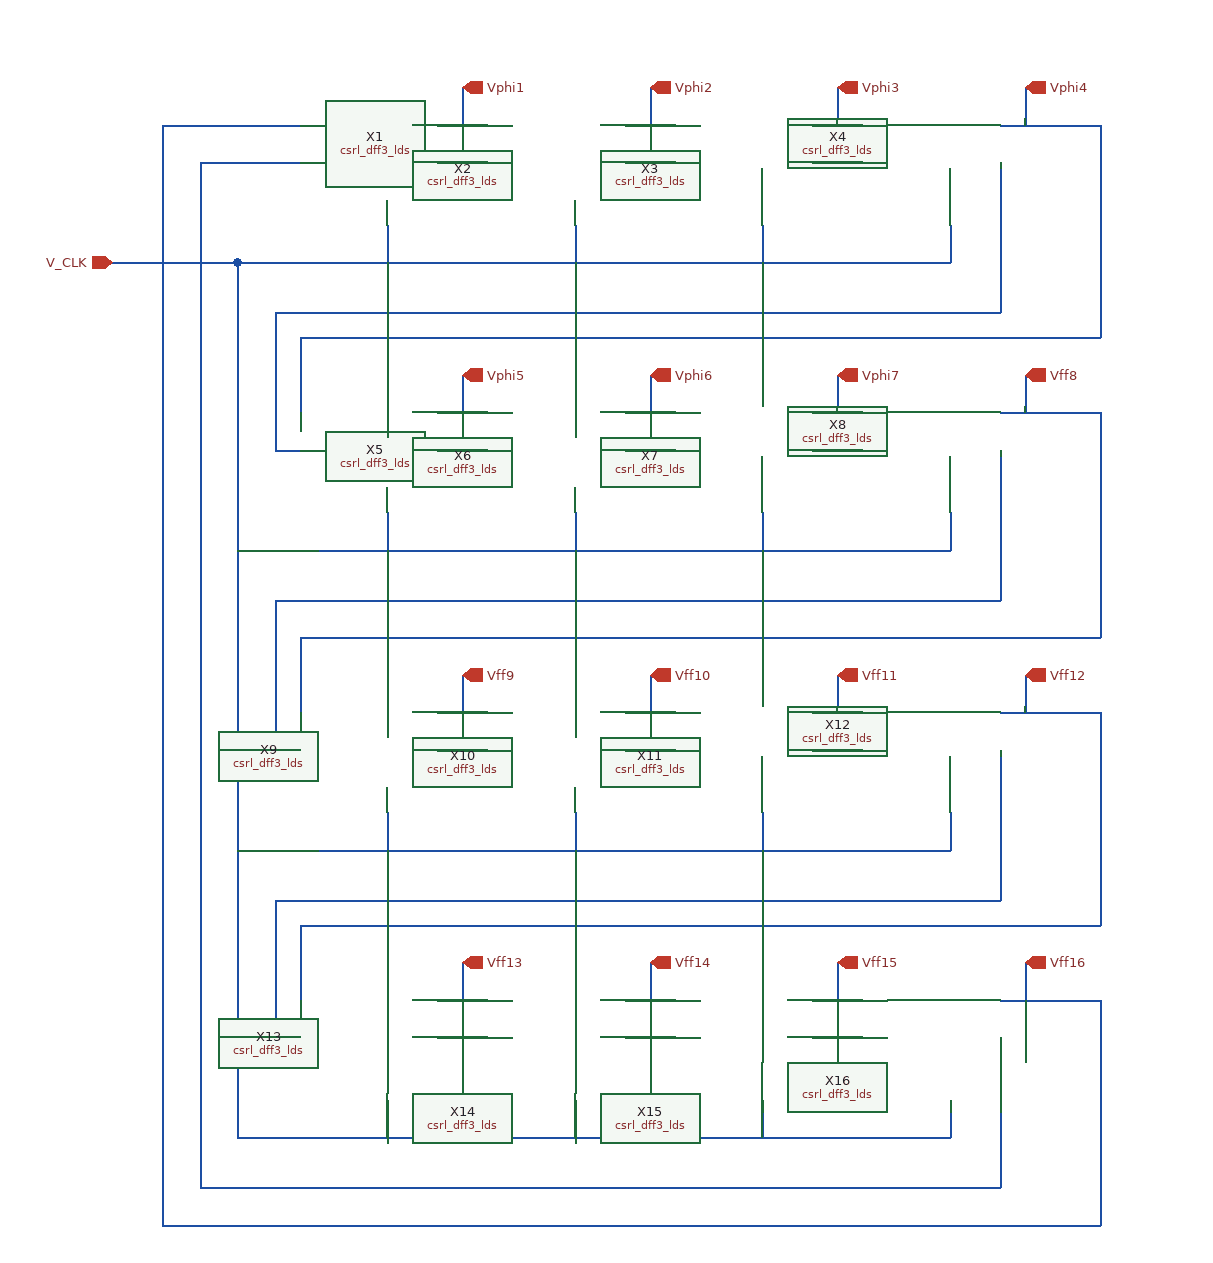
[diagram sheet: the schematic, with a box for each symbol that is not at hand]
v {xschem version=3.4.3 file_version=1.2
}
G {}
K {}
V {}
S {}
E {}
N -10 130 460 130 {
lab=V_CLK}
N 460 100 460 130 {
lab=V_CLK}
N -10 360 460 360 {
lab=V_CLK}
N 460 330 460 360 {
lab=V_CLK}
N 580 140 580 190 {
lab=Vphi4}
N -60 190 580 190 {
lab=Vphi4}
N -80 170 -80 280 {
lab=#net1}
N -80 280 -60 280 {
lab=#net1}
N -10 600 460 600 {
lab=V_CLK}
N 10 570 10 600 {
lab=V_CLK}
N 460 570 460 600 {
lab=V_CLK}
N -10 830 460 830 {
lab=V_CLK}
N 460 800 460 830 {
lab=V_CLK}
N -60 660 580 660 {
lab=Vff12}
N -80 640 -80 750 {
lab=#net2}
N -80 750 -60 750 {
lab=#net2}
N 580 370 580 430 {
lab=Vff8}
N -60 430 580 430 {
lab=Vff8}
N -80 400 -80 520 {
lab=#net3}
N -80 520 -60 520 {
lab=#net3}
N -140 50 -140 870 {
lab=#net4}
N 580 840 580 900 {
lab=Vff16}
N -170 20 -170 900 {
lab=Vff16}
N -60 190 -60 250 {
lab=Vphi4}
N -60 430 -60 490 {
lab=Vff8}
N -60 660 -60 720 {
lab=Vff12}
N 500 50 500 170 {
lab=#net1}
N -80 170 500 170 {
lab=#net1}
N 580 20 580 140 {
lab=Vphi4}
N 580 250 580 370 {
lab=Vff8}
N -80 400 500 400 {
lab=#net3}
N 500 280 500 400 {
lab=#net3}
N 580 490 580 660 {
lab=Vff12}
N 500 520 500 640 {
lab=#net2}
N -80 640 500 640 {
lab=#net2}
N 580 720 580 840 {
lab=Vff16}
N 500 750 500 870 {
lab=#net4}
N -170 20 -60 20 {
lab=Vff16}
N -140 50 -60 50 {
lab=#net4}
N -140 870 500 870 {
lab=#net4}
N -170 900 580 900 {
lab=Vff16}
N -110 130 -10 130 {
lab=V_CLK}
N -110 130 -110 830 {
lab=V_CLK}
N -110 830 -10 830 {
lab=V_CLK}
N -110 600 -10 600 {
lab=V_CLK}
N -110 360 -10 360 {
lab=V_CLK}
N -210 130 -110 130 {
lab=V_CLK}
N 500 20 580 20 {
lab=Vphi4}
N 500 250 580 250 {
lab=Vff8}
N 500 490 580 490 {
lab=Vff12}
N 500 720 580 720 {
lab=Vff16}
N 310 330 310 360 {
lab=V_CLK}
N 160 330 160 360 {
lab=V_CLK}
N 10 330 10 360 {
lab=V_CLK}
N 10 100 10 130 {
lab=V_CLK}
N 160 100 160 130 {
lab=V_CLK}
N 310 100 310 130 {
lab=V_CLK}
N 310 570 310 600 {
lab=V_CLK}
N 160 570 160 600 {
lab=V_CLK}
N 10 800 10 830 {
lab=V_CLK}
N 310 800 310 830 {
lab=V_CLK}
N 160 800 160 830 {
lab=V_CLK}
N 50 20 90 20 {
lab=Vphi1}
N 50 50 90 50 {
lab=#net5}
N 200 20 240 20 {
lab=Vphi2}
N 200 50 240 50 {
lab=#net6}
N 350 20 390 20 {
lab=Vphi3}
N 350 50 390 50 {
lab=#net7}
N 350 250 390 250 {
lab=Vphi7}
N 350 280 390 280 {
lab=#net8}
N 200 250 240 250 {
lab=Vphi6}
N 200 280 240 280 {
lab=#net9}
N 50 280 90 280 {
lab=#net10}
N 50 250 90 250 {
lab=Vphi5}
N 50 520 90 520 {
lab=#net11}
N 50 490 90 490 {
lab=Vff9}
N 200 520 240 520 {
lab=#net12}
N 200 490 240 490 {
lab=Vff10}
N 350 520 390 520 {
lab=#net13}
N 350 490 390 490 {
lab=Vff11}
N 350 750 390 750 {
lab=#net14}
N 350 720 390 720 {
lab=Vff15}
N 200 750 240 750 {
lab=#net15}
N 200 720 240 720 {
lab=Vff14}
N 50 750 90 750 {
lab=#net16}
N 50 720 90 720 {
lab=Vff13}
N 70 -10 70 20 {
lab=Vphi1}
N 220 -10 220 20 {
lab=Vphi2}
N 370 -10 370 20 {
lab=Vphi3}
N 70 220 70 250 {
lab=Vphi5}
N 220 220 220 250 {
lab=Vphi6}
N 370 220 370 250 {
lab=Vphi7}
N 520 -10 520 20 {
lab=Vphi4}
N 520 220 520 250 {
lab=Vff8}
N 520 460 520 490 {
lab=Vff12}
N 520 690 520 720 {
lab=Vff16}
N 70 460 70 490 {
lab=Vff9}
N 220 460 220 490 {
lab=Vff10}
N 370 460 370 490 {
lab=Vff11}
N 370 690 370 720 {
lab=Vff15}
N 220 690 220 720 {
lab=Vff14}
N 70 690 70 720 {
lab=Vff13}
C {/home/madvlsi/VLSI_Sine_Gen/simulation/shift_register/lauren_mp2_files/csrl_dff3_lds.sym} -130 0 0 0 {name=X1}
C {/home/madvlsi/VLSI_Sine_Gen/simulation/shift_register/lauren_mp2_files/csrl_dff3_lds.sym} 20 0 0 0 {name=X2}
C {/home/madvlsi/VLSI_Sine_Gen/simulation/shift_register/lauren_mp2_files/csrl_dff3_lds.sym} 170 0 0 0 {name=X3}
C {/home/madvlsi/VLSI_Sine_Gen/simulation/shift_register/lauren_mp2_files/csrl_dff3_lds.sym} 320 0 0 0 {name=X4}
C {/home/madvlsi/VLSI_Sine_Gen/simulation/shift_register/lauren_mp2_files/csrl_dff3_lds.sym} -130 230 0 0 {name=X5}
C {/home/madvlsi/VLSI_Sine_Gen/simulation/shift_register/lauren_mp2_files/csrl_dff3_lds.sym} 20 230 0 0 {name=X6}
C {/home/madvlsi/VLSI_Sine_Gen/simulation/shift_register/lauren_mp2_files/csrl_dff3_lds.sym} 170 230 0 0 {name=X7}
C {/home/madvlsi/VLSI_Sine_Gen/simulation/shift_register/lauren_mp2_files/csrl_dff3_lds.sym} 320 230 0 0 {name=X8}
C {/home/madvlsi/VLSI_Sine_Gen/simulation/shift_register/lauren_mp2_files/csrl_dff3_lds.sym} -130 470 0 0 {name=X9}
C {/home/madvlsi/VLSI_Sine_Gen/simulation/shift_register/lauren_mp2_files/csrl_dff3_lds.sym} 20 470 0 0 {name=X10}
C {/home/madvlsi/VLSI_Sine_Gen/simulation/shift_register/lauren_mp2_files/csrl_dff3_lds.sym} 170 470 0 0 {name=X11}
C {/home/madvlsi/VLSI_Sine_Gen/simulation/shift_register/lauren_mp2_files/csrl_dff3_lds.sym} 320 470 0 0 {name=X12}
C {/home/madvlsi/VLSI_Sine_Gen/simulation/shift_register/lauren_mp2_files/csrl_dff3_lds.sym} -130 700 0 0 {name=X13}
C {/home/madvlsi/VLSI_Sine_Gen/simulation/shift_register/lauren_mp2_files/csrl_dff3_lds.sym} 20 700 0 0 {name=X14}
C {/home/madvlsi/VLSI_Sine_Gen/simulation/shift_register/lauren_mp2_files/csrl_dff3_lds.sym} 170 700 0 0 {name=X15}
C {/home/madvlsi/VLSI_Sine_Gen/simulation/shift_register/lauren_mp2_files/csrl_dff3_lds.sym} 320 700 0 0 {name=X16}
C {devices/opin.sym} 70 -10 0 0 {name=p1 lab=Vphi1}
C {devices/opin.sym} 220 -10 0 0 {name=p3 lab=Vphi2}
C {devices/opin.sym} 370 -10 0 0 {name=p4 lab=Vphi3}
C {devices/opin.sym} 520 -10 0 0 {name=p5 lab=Vphi4}
C {devices/opin.sym} 70 220 0 0 {name=p6 lab=Vphi5}
C {devices/opin.sym} 220 220 0 0 {name=p7 lab=Vphi6}
C {devices/opin.sym} 370 220 0 0 {name=p8 lab=Vphi7}
C {devices/opin.sym} 520 220 0 0 {name=p9 lab=Vff8}
C {devices/opin.sym} 70 460 0 0 {name=p10 lab=Vff9}
C {devices/opin.sym} 220 460 0 0 {name=p11 lab=Vff10}
C {devices/opin.sym} 370 460 0 0 {name=p12 lab=Vff11}
C {devices/opin.sym} 520 460 0 0 {name=p13 lab=Vff12}
C {devices/opin.sym} 70 690 0 0 {name=p14 lab=Vff13}
C {devices/opin.sym} 220 690 0 0 {name=p15 lab=Vff14}
C {devices/opin.sym} 370 690 0 0 {name=p16 lab=Vff15}
C {devices/opin.sym} 520 690 0 0 {name=p17 lab=Vff16}
C {devices/ipin.sym} -210 130 0 0 {name=p2 lab=V_CLK}
